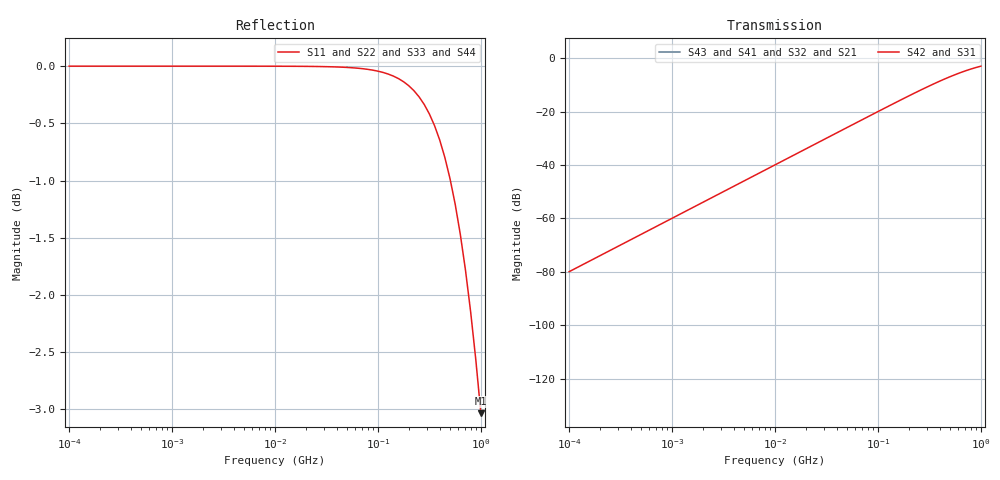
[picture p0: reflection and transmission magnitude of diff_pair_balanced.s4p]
# Hz S RI R 50
! golden: diff_pair_balanced
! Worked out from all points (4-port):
!   81 points, 100 kHz to 1 GHz, reference 50 ohm
!   strongest paths, dB at 100 kHz, 1 MHz, 10 MHz, 100 MHz, 1 GHz:
!     S42: -80.0, -60.0, -40.0, -20.0, -3.0
!     S31: -80.0, -60.0, -40.0, -20.0, -3.0
!     S43: -, -, -, -, -
!     S41: -, -, -, -, -
!     S32: -, -, -, -, -
!     S21: -, -, -, -, -
!   lowest |S11| = -3.0 dB at 1 GHz (marker M1), VSWR 5.78, Z = 10.1 + j20.1 ohm
!   |S11| at or under -10 dB: nowhere
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100000  -1 0.000101  0 0  -1.01e-08 -0.000101  0 0
        0 0  -1 0.000101  0 0  -1.01e-08 -0.000101
        -1.01e-08 -0.000101  0 0  -1 0.000101  0 0
        0 0  -1.01e-08 -0.000101  0 0  -1 0.000101
2.238721e7  -0.9995 0.0225  0 0  -0.000506 -0.0225  0 0
            0 0  -0.9995 0.0225  0 0  -0.000506 -0.0225
            -0.000506 -0.0225  0 0  -0.9995 0.0225  0 0
            0 0  -0.000506 -0.0225  0 0  -0.9995 0.0225
7.079458e7  -0.995 0.0708  0 0  -0.00504 -0.0708  0 0
            0 0  -0.995 0.0708  0 0  -0.00504 -0.0708
            -0.00504 -0.0708  0 0  -0.995 0.0708  0 0
            0 0  -0.00504 -0.0708  0 0  -0.995 0.0708
1.778279e8  -0.969 0.1732  0 0  -0.031 -0.1732  0 0
            0 0  -0.969 0.1732  0 0  -0.031 -0.1732
            -0.031 -0.1732  0 0  -0.969 0.1732  0 0
            0 0  -0.031 -0.1732  0 0  -0.969 0.1732
4.466836e8  -0.8322 0.3737  0 0  -0.1678 -0.3737  0 0
            0 0  -0.8322 0.3737  0 0  -0.1678 -0.3737
            -0.1678 -0.3737  0 0  -0.8322 0.3737  0 0
            0 0  -0.1678 -0.3737  0 0  -0.8322 0.3737
7.079458e8  -0.6638 0.4724  0 0  -0.3362 -0.4724  0 0
            0 0  -0.6638 0.4724  0 0  -0.3362 -0.4724
            -0.3362 -0.4724  0 0  -0.6638 0.4724  0 0
            0 0  -0.3362 -0.4724  0 0  -0.6638 0.4724
1e9  -0.4974 0.5  0 0  -0.5026 -0.5  0 0
     0 0  -0.4974 0.5  0 0  -0.5026 -0.5
     -0.5026 -0.5  0 0  -0.4974 0.5  0 0
     0 0  -0.5026 -0.5  0 0  -0.4974 0.5
